VERSION 5.7 ;
  NOWIREEXTENSIONATPIN ON ;
  DIVIDERCHAR "/" ;
  BUSBITCHARS "[]" ;
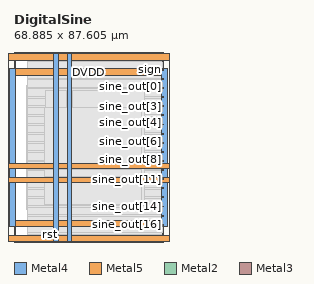
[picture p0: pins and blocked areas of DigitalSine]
MACRO DigitalSine
  CLASS BLOCK ;
  FOREIGN DigitalSine ;
  ORIGIN 0.000 0.000 ;
  SIZE 68.885 BY 87.605 ;
  PIN DVDD
    DIRECTION INOUT ;
    USE POWER ;
    PORT
      LAYER Metal4 ;
        RECT -2.240 7.120 0.760 79.820 ;
    END
    PORT
      LAYER Metal5 ;
        RECT -2.240 7.120 70.880 10.120 ;
    END
    PORT
      LAYER Metal5 ;
        RECT -2.240 76.820 70.880 79.820 ;
    END
    PORT
      LAYER Metal4 ;
        RECT 67.880 7.120 70.880 79.820 ;
    END
    PORT
      LAYER Metal4 ;
        RECT 18.260 0.120 20.460 86.820 ;
    END
    PORT
      LAYER Metal5 ;
        RECT -9.240 27.620 77.880 29.820 ;
    END
  END DVDD
  PIN DVSS
    DIRECTION INOUT ;
    USE GROUND ;
    PORT
      LAYER Metal4 ;
        RECT -9.240 0.120 -6.240 86.820 ;
    END
    PORT
      LAYER Metal5 ;
        RECT -9.240 0.120 77.880 3.120 ;
    END
    PORT
      LAYER Metal5 ;
        RECT -9.240 83.820 77.880 86.820 ;
    END
    PORT
      LAYER Metal4 ;
        RECT 74.880 0.120 77.880 86.820 ;
    END
    PORT
      LAYER Metal4 ;
        RECT 24.460 0.120 26.660 86.820 ;
    END
    PORT
      LAYER Metal5 ;
        RECT -9.240 33.820 77.880 36.020 ;
    END
  END DVSS
  PIN clk
    DIRECTION INPUT ;
    USE SIGNAL ;
    ANTENNAGATEAREA 0.725400 ;
    PORT
      LAYER Metal2 ;
        RECT 51.160 0.000 51.560 0.400 ;
    END
  END clk
  PIN rst
    DIRECTION INPUT ;
    USE SIGNAL ;
    ANTENNAGATEAREA 0.180700 ;
    PORT
      LAYER Metal2 ;
        RECT 16.600 0.000 17.000 0.400 ;
    END
  END rst
  PIN sign
    DIRECTION OUTPUT ;
    USE SIGNAL ;
    ANTENNADIFFAREA 0.706800 ;
    PORT
      LAYER Metal3 ;
        RECT 68.485 79.180 68.885 79.580 ;
    END
  END sign
  PIN signB
    DIRECTION OUTPUT ;
    USE SIGNAL ;
    ANTENNADIFFAREA 0.706800 ;
    PORT
      LAYER Metal3 ;
        RECT 68.485 83.380 68.885 83.780 ;
    END
  END signB
  PIN sine_out[0]
    DIRECTION OUTPUT ;
    USE SIGNAL ;
    ANTENNADIFFAREA 0.708600 ;
    PORT
      LAYER Metal3 ;
        RECT 68.485 74.980 68.885 75.380 ;
    END
  END sine_out[0]
  PIN sine_out[10]
    DIRECTION OUTPUT ;
    USE SIGNAL ;
    ANTENNADIFFAREA 0.708600 ;
    PORT
      LAYER Metal3 ;
        RECT 68.485 32.980 68.885 33.380 ;
    END
  END sine_out[10]
  PIN sine_out[11]
    DIRECTION OUTPUT ;
    USE SIGNAL ;
    ANTENNADIFFAREA 0.708600 ;
    PORT
      LAYER Metal3 ;
        RECT 68.485 28.780 68.885 29.180 ;
    END
  END sine_out[11]
  PIN sine_out[12]
    DIRECTION OUTPUT ;
    USE SIGNAL ;
    ANTENNADIFFAREA 0.708600 ;
    PORT
      LAYER Metal3 ;
        RECT 68.485 24.580 68.885 24.980 ;
    END
  END sine_out[12]
  PIN sine_out[13]
    DIRECTION OUTPUT ;
    USE SIGNAL ;
    ANTENNADIFFAREA 0.708600 ;
    PORT
      LAYER Metal3 ;
        RECT 68.485 20.380 68.885 20.780 ;
    END
  END sine_out[13]
  PIN sine_out[14]
    DIRECTION OUTPUT ;
    USE SIGNAL ;
    ANTENNADIFFAREA 0.708600 ;
    PORT
      LAYER Metal3 ;
        RECT 68.485 16.180 68.885 16.580 ;
    END
  END sine_out[14]
  PIN sine_out[15]
    DIRECTION OUTPUT ;
    USE SIGNAL ;
    ANTENNADIFFAREA 0.708600 ;
    PORT
      LAYER Metal3 ;
        RECT 68.485 11.980 68.885 12.380 ;
    END
  END sine_out[15]
  PIN sine_out[16]
    DIRECTION OUTPUT ;
    USE SIGNAL ;
    ANTENNADIFFAREA 0.708600 ;
    PORT
      LAYER Metal3 ;
        RECT 68.485 7.780 68.885 8.180 ;
    END
  END sine_out[16]
  PIN sine_out[17]
    DIRECTION OUTPUT ;
    USE SIGNAL ;
    ANTENNADIFFAREA 0.708600 ;
    PORT
      LAYER Metal3 ;
        RECT 68.485 3.580 68.885 3.980 ;
    END
  END sine_out[17]
  PIN sine_out[1]
    DIRECTION OUTPUT ;
    USE SIGNAL ;
    ANTENNADIFFAREA 0.708600 ;
    PORT
      LAYER Metal3 ;
        RECT 68.485 70.780 68.885 71.180 ;
    END
  END sine_out[1]
  PIN sine_out[2]
    DIRECTION OUTPUT ;
    USE SIGNAL ;
    ANTENNADIFFAREA 0.708600 ;
    PORT
      LAYER Metal3 ;
        RECT 68.485 66.580 68.885 66.980 ;
    END
  END sine_out[2]
  PIN sine_out[3]
    DIRECTION OUTPUT ;
    USE SIGNAL ;
    ANTENNADIFFAREA 0.708600 ;
    PORT
      LAYER Metal3 ;
        RECT 68.485 62.380 68.885 62.780 ;
    END
  END sine_out[3]
  PIN sine_out[4]
    DIRECTION OUTPUT ;
    USE SIGNAL ;
    ANTENNADIFFAREA 0.708600 ;
    PORT
      LAYER Metal3 ;
        RECT 68.485 58.180 68.885 58.580 ;
    END
  END sine_out[4]
  PIN sine_out[5]
    DIRECTION OUTPUT ;
    USE SIGNAL ;
    ANTENNADIFFAREA 0.708600 ;
    PORT
      LAYER Metal3 ;
        RECT 68.485 53.980 68.885 54.380 ;
    END
  END sine_out[5]
  PIN sine_out[6]
    DIRECTION OUTPUT ;
    USE SIGNAL ;
    ANTENNADIFFAREA 0.708600 ;
    PORT
      LAYER Metal3 ;
        RECT 68.485 49.780 68.885 50.180 ;
    END
  END sine_out[6]
  PIN sine_out[7]
    DIRECTION OUTPUT ;
    USE SIGNAL ;
    ANTENNADIFFAREA 0.708600 ;
    PORT
      LAYER Metal3 ;
        RECT 68.485 45.580 68.885 45.980 ;
    END
  END sine_out[7]
  PIN sine_out[8]
    DIRECTION OUTPUT ;
    USE SIGNAL ;
    ANTENNADIFFAREA 0.708600 ;
    PORT
      LAYER Metal3 ;
        RECT 68.485 41.380 68.885 41.780 ;
    END
  END sine_out[8]
  PIN sine_out[9]
    DIRECTION OUTPUT ;
    USE SIGNAL ;
    ANTENNADIFFAREA 0.708600 ;
    PORT
      LAYER Metal3 ;
        RECT 68.485 37.180 68.885 37.580 ;
    END
  END sine_out[9]
  OBS
      LAYER GatPoly ;
        RECT 5.760 14.970 62.880 71.970 ;
      LAYER Metal1 ;
        RECT 5.760 14.900 62.880 72.040 ;
      LAYER Metal2 ;
        RECT 6.135 0.610 67.305 83.725 ;
        RECT 6.135 0.100 16.390 0.610 ;
        RECT 17.210 0.100 50.950 0.610 ;
        RECT 51.770 0.100 67.305 0.610 ;
      LAYER Metal3 ;
        RECT 6.095 83.170 68.275 83.680 ;
        RECT 6.095 79.790 68.485 83.170 ;
        RECT 6.095 78.970 68.275 79.790 ;
        RECT 6.095 75.590 68.485 78.970 ;
        RECT 6.095 74.770 68.275 75.590 ;
        RECT 6.095 71.390 68.485 74.770 ;
        RECT 6.095 70.570 68.275 71.390 ;
        RECT 6.095 67.190 68.485 70.570 ;
        RECT 6.095 66.370 68.275 67.190 ;
        RECT 6.095 62.990 68.485 66.370 ;
        RECT 6.095 62.170 68.275 62.990 ;
        RECT 6.095 58.790 68.485 62.170 ;
        RECT 6.095 57.970 68.275 58.790 ;
        RECT 6.095 54.590 68.485 57.970 ;
        RECT 6.095 53.770 68.275 54.590 ;
        RECT 6.095 50.390 68.485 53.770 ;
        RECT 6.095 49.570 68.275 50.390 ;
        RECT 6.095 46.190 68.485 49.570 ;
        RECT 6.095 45.370 68.275 46.190 ;
        RECT 6.095 41.990 68.485 45.370 ;
        RECT 6.095 41.170 68.275 41.990 ;
        RECT 6.095 37.790 68.485 41.170 ;
        RECT 6.095 36.970 68.275 37.790 ;
        RECT 6.095 33.590 68.485 36.970 ;
        RECT 6.095 32.770 68.275 33.590 ;
        RECT 6.095 29.390 68.485 32.770 ;
        RECT 6.095 28.570 68.275 29.390 ;
        RECT 6.095 25.190 68.485 28.570 ;
        RECT 6.095 24.370 68.275 25.190 ;
        RECT 6.095 20.990 68.485 24.370 ;
        RECT 6.095 20.170 68.275 20.990 ;
        RECT 6.095 16.790 68.485 20.170 ;
        RECT 6.095 15.970 68.275 16.790 ;
        RECT 6.095 12.590 68.485 15.970 ;
        RECT 6.095 11.770 68.275 12.590 ;
        RECT 6.095 8.390 68.485 11.770 ;
        RECT 6.095 7.570 68.275 8.390 ;
        RECT 6.095 4.190 68.485 7.570 ;
        RECT 6.095 3.370 68.275 4.190 ;
        RECT 6.095 2.420 68.485 3.370 ;
      LAYER Metal4 ;
        RECT 14.295 16.650 18.050 69.865 ;
        RECT 20.670 16.650 24.250 69.865 ;
        RECT 26.870 16.650 60.100 69.865 ;
      LAYER Metal5 ;
        RECT 14.255 36.230 58.705 61.840 ;
        RECT 14.255 30.030 58.705 33.610 ;
        RECT 14.255 17.120 58.705 27.410 ;
  END
END DigitalSine
END LIBRARY

